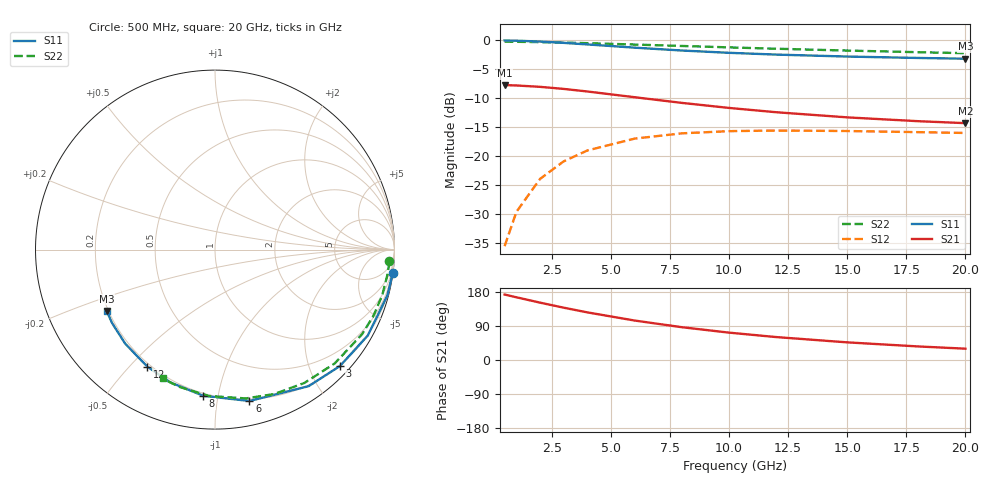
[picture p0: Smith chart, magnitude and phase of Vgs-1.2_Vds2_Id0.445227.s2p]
# Hz S RI R 50
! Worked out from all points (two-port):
!   12 points, 500 MHz to 20 GHz, reference 50 ohm
!   highest |S21| = -7.74 dB at 500 MHz (marker M1); lowest = -14.3 dB at 20 GHz (marker M2)
!   |S21| within 3 dB of the highest: start of sweep to 7.845 GHz
!   lowest |S11| = -3.2 dB at 20 GHz (marker M3), VSWR 5.54, Z = 9.63 - j12.7 ohm
!   |S11| at or under -10 dB: nowhere
!   |S22| runs from -2.2 to -0.2 dB; largest |S21 - S12| = 0.41
!   S11 on the Smith chart (normalised r, x): 500 MHz: 0, -15; 3 GHz: 0.18, -2.53; 6 GHz: 0.18, -1.24; 8 GHz: 0.18, -0.91; 12 GHz: 0.19, -0.56; 20 GHz: 0.19, -0.25
5e8  0.9899 -0.1302  -0.4069 0.0521  0.00158 0.0165  0.9713 -0.0656
1e9  0.9602 -0.256  -0.3943 0.1022  0.00621 0.0323  0.9632 -0.1304
2e9  0.8508 -0.4792  -0.3479 0.1899  0.0231 0.059  0.9315 -0.2553
3e9  0.6959 -0.6489  -0.2828 0.2542  0.0465 0.0768  0.8824 -0.3698
4e9  0.5218 -0.7608  -0.2108 0.2935  0.0719 0.0852  0.8193 -0.472
6e9  0.1919 -0.8434  -0.0788 0.3125  0.1161 0.0804  0.6669 -0.6342
8e9  -0.0654 -0.8144  0.0174 0.2874  0.1447 0.0609  0.4981 -0.743
1e10  -0.2487 -0.7399  0.0796 0.2479  0.1594 0.0386  0.33 -0.8048
1.2e10  -0.3765 -0.6526  0.1178 0.2079  0.165 0.0183  0.1722 -0.8292
1.5e10  -0.4998 -0.5247  0.1484 0.1566  0.1643 -0.00554  -0.0345 -0.8155
1.8e10  -0.5726 -0.4105  0.1622 0.1169  0.1592 -0.0223  -0.2014 -0.764
2e10  -0.6038 -0.3425  0.1667 0.0958  0.1551 -0.0306  -0.292 -0.7177
